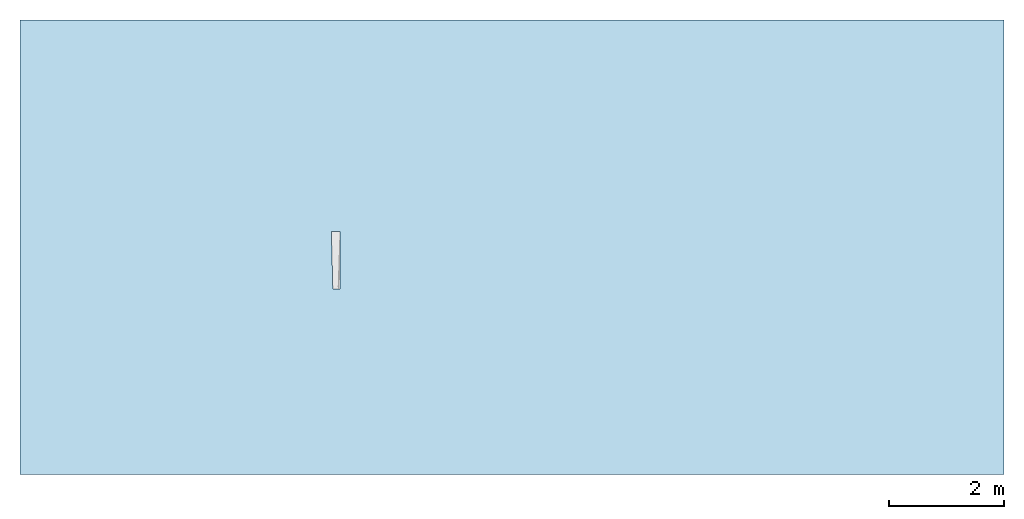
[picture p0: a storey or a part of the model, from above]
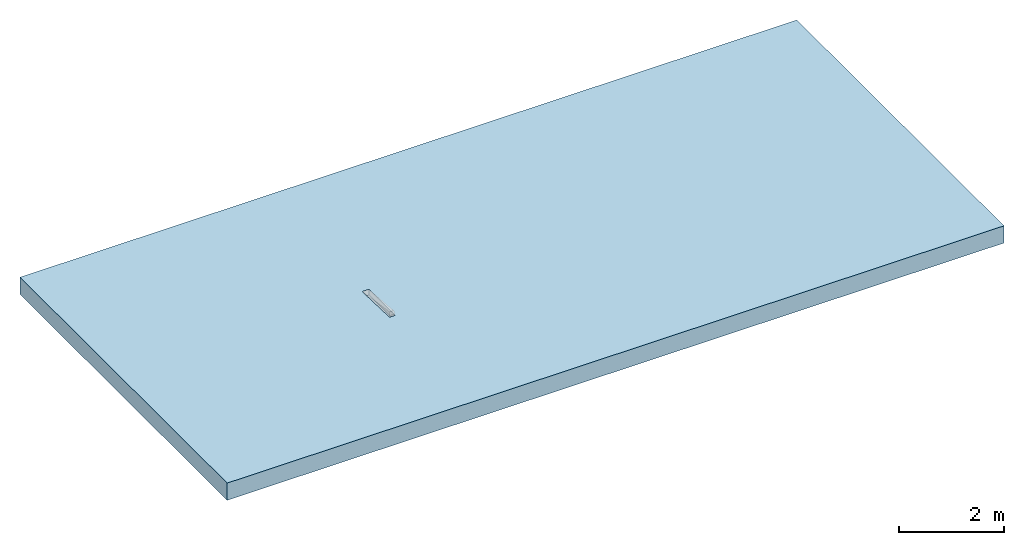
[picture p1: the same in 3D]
Properties of the parts of a building model (IFC2X3)

# File
Description: ViewDefinition [CoordinationView]
File name: 7956 - LH drop kerb - 1000mm LG.ifc
Time: 2013-08-30T17:41:29
Written by: Autodesk Revit 2013
Made in: 20120221_2030(x64)

# IfcProject, Project Number
LongName: Project Name; Phase: Project Status

# IfcSite, Default
RefLatitude: 42, 21, 30, 344238; RefLongitude: -71, -3, -35, -194702; RefElevation: 0 mm

# IfcBuilding
Pset_BuildingCommon - NumberOfStoreys: 1
Other - Project Number: Project Number; Project Status: Project Status; Project Issue Date: Issue Date; Project Name: Project Name; Project Address: ## Street City, State Zip; Client Name: Owner

# IfcBuildingStorey, Level 1
LongName: Level 1; Elevation: 0 mm
Constraints - Elevation Base: 0; Elevation: 0 mm
Graphics - Line Pattern: Center; Color: 0; Symbol: M_Level Head - Circle: M_Level Head - Circle; Symbol at End 2 Default: yes; Line Weight: 1; Symbol at End 1 Default: no
Identity Data - Structural: no; Name: Level 1; Building Story: yes
Dimensions - Computation Height: 0 mm

# IfcBuildingElementProxy: 7956 - LH drop kerb - 1000mm LG, Civil-Drainage-Channel-ACO-KerbDrain-HB255:7956 - LH drop kerb - 1000mm LG:7956 - LH drop kerb - 1000mm LG:754467
In: Level 1
Material: ACO Polymer Concrete.
Phasing - Phase Created: New Construction
Constraints - Moves With Nearby Elements: no; Level: Level: Level 1
Dimensions - Volume: 17724615 mm3; RH Void Start: -2000 mm; RH Hole End: -2005 mm; LH Void End: 0 mm; LH Void Start: -130 mm; Access Depth: 2000 mm; Void Depth: -2005 mm; Void Width: 150 mm; Void Start: -2000 mm; Void Length: 1000 mm
Pset_BuildingElementProxyCommon - Reference: 7956 - LH drop kerb - 1000mm LG
Identity Data - OmniClass Number: 23.70.50.24; Maintenance guidelines: http://www.aco.co.uk/download.php?id=120; OmniClass Title: Rainwater Removal; Price: POA - contact ACO; e-mail Sales: customersupport@aco.co.uk; Telephone: +44 (0)1462 816666; Installation guidelines: http://www.aco.co.uk/download.php?id=120; URL: www.aco.co.uk; Product Code: 7956; Assembly Code: D2040; Model Description: Combined kerb and drainage system; Product Page URL: http://www.aco.co.uk/product_detail.php?id=3; Product brochure: http://www.aco.co.uk/download.php?id=120; e-mail Technical: technical@aco.co.uk; Fax: +44 (0)1462 815895; Address: ACO Business Park, Hitchin Road, Shefford, Bedfordshire, United Kingdom SG17 5TE; Manufacturer: ACO Technologies plc - ACO Water Management Division; Assembly Description: Rain Water Drainage; Type Comments: ACO KerbDrain HB255 half battered left-hand drop kerb unit 1000mm long; Cost: 0; Model: ACO KerbDrain HB255
Materials and Finishes - End Cap Material: N/A; Channel Material: Vienite® Synthetic Resin Concrete; Access Cover/Frame Finish: N/A; End Cap Colour: N/A; Access Cover/Frame Material: N/A; Access Cover/Frame Colour: N/A; Channel Colour: Grey
Green Building Properties - Access Cover/Frame Recyclable: N/A; End Cap Recycled Material Content: N/A; Channel Recycled Material Content: 20% minimum; End Cap Recyclable: N/A; Channel Recyclable: Fully recyclable; Access Cover/Frame Recycled Material Content: N/A
Construction - HB255 - 500: no; Centre Stone: no; RH drop kerb: no; HB255 - 1000: no; Access Unit: no; Closing end cap: no; LH drop kerb: yes
Data - Product Weight: 38.0 Kg; Invert Depth: 235/105mm; Hydraulic Performance: http://www.aco.co.uk/download.php?id=120; Load Class: A 15 - D 400; Channel C.S.A: 0.01 to 0.005m²; ACO Hydraulic Design Software: http://www.acodesign.co.uk; Concrete Surround Volume - Load Class A 15 - D 400 - Grass or Asphalt Pavement: N/A; Concrete Surround Volume - Load Class A 15 - D 400 - Concrete Pavement: N/A; Product Dimensions: 1000mm x 125/150mm x 255/130mm (LxWxH); Drainage Slot Intake area: N/A; Drainage Slot Width: N/A; Connection Pipe O.D: N/A; Installation - Concrete Grade: Refer to brochure; Product Standard: BS EN 1433:2002, CE marked, Kitemarked
Other - CreatedBy: www.aco.co.uk; Revision: 1
General - TagNumber: 0.000000; SerialNumber: 0.000000

# IfcOpeningElement: Recess (3)
In: Level 1
Dimensions - Area: 135090000 mm2; Perimeter: 50000 mm; Volume: 54018125000 mm3; Thickness: 400 mm
Structural - Structural: no; Enable Analytical Model: no
Constraints - Room Bounding: yes; Height Offset From Level: 0 mm; Level: Level: Level 1; Related to Mass: no
Phasing - Phase Created: New Construction
Analytical Properties - Roughness: 1; Absorptance: 0.1
Construction - Function: 0; Default Thickness: 400 mm
Graphics - Coarse Scale Fill Color: 0
Materials and Finishes - Structural Material: Plant

# IfcSlab: Floor:Generic Floor - 400mm, Floor:Generic Floor - 400mm:193825
In: Level 1
PredefinedType: FLOOR; Material: Plant 400 mm
Dimensions - Area: 135090000 mm2; Perimeter: 50000 mm; Volume: 54018125000 mm3; Thickness: 400 mm
Structural - Structural: no; Enable Analytical Model: no
Constraints - Room Bounding: yes; Height Offset From Level: 0 mm; Level: Level: Level 1; Related to Mass: no
Phasing - Phase Created: New Construction
Pset_SlabCommon - Reference: Generic Floor - 400mm; IsExternal: no; LoadBearing: yes
Analytical Properties - Roughness: 1; Absorptance: 0.1
Construction - Function: 0; Default Thickness: 400 mm
Graphics - Coarse Scale Fill Color: 0
Materials and Finishes - Structural Material: Plant
